VERSION 5.7 ;
BUSBITCHARS "[]" ;
DIVIDERCHAR "/" ;

# Double-height CORE cell with symmetric power (VSS at bottom, VDD in
# middle, VSS at top).  Modeled on a flop cell that has to land on every
# other row; when placed starting at an MX (FS) row, its VDD pin would
# sit on top of a VSS stripe.  Exercises dpl's multi-row power
# compatibility check.
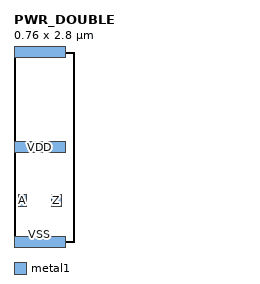
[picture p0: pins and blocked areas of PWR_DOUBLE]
MACRO PWR_DOUBLE
  CLASS CORE ;
  ORIGIN 0 0 ;
  SIZE 0.76 BY 2.8 ;
  SYMMETRY X Y ;
  SITE FreePDK45_38x28_10R_NP_162NW_34O ;
  PIN A
    DIRECTION INPUT ;
    USE SIGNAL ;
    PORT
      LAYER metal1 ;
        RECT 0.06 0.525 0.185 0.7 ;
    END
  END A
  PIN Z
    DIRECTION OUTPUT ;
    USE SIGNAL ;
    PORT
      LAYER metal1 ;
        RECT 0.55 0.525 0.7 0.7 ;
    END
  END Z
  PIN VDD
    DIRECTION INOUT ;
    USE POWER ;
    SHAPE ABUTMENT ;
    PORT
      LAYER metal1 ;
        RECT 0 1.315 0.76 1.485 ;
    END
  END VDD
  PIN VSS
    DIRECTION INOUT ;
    USE GROUND ;
    SHAPE ABUTMENT ;
    PORT
      LAYER metal1 ;
        RECT 0 -0.085 0.76 0.085 ;
        RECT 0 2.715 0.76 2.885 ;
    END
  END VSS
END PWR_DOUBLE

END LIBRARY
